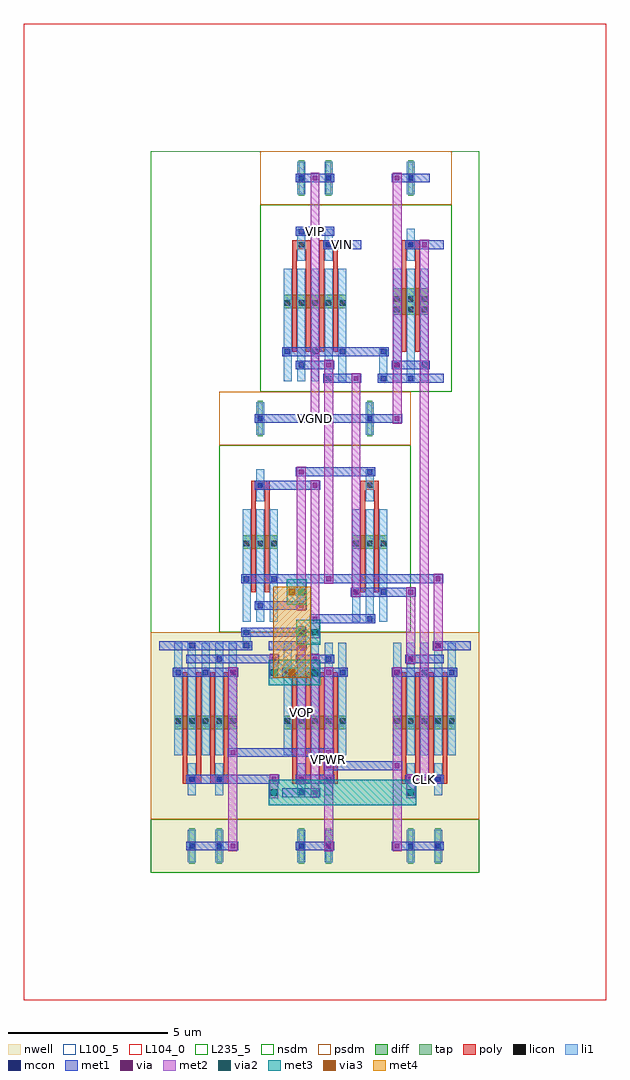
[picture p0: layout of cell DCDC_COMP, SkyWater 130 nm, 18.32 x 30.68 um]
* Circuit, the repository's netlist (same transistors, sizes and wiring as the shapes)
.subckt DCDC_COMP VPWR VGND VIN VIP VOP CLK
X0 VCM CLK VGND VGND  sky130_fd_pr__nfet_01v8 w=840000u l=150000u m=2
X1 VMP VIN VCM VGND  sky130_fd_pr__nfet_01v8 w=420000u l=150000u m=2
X2 VMN VIP VCM VGND  sky130_fd_pr__nfet_01v8 w=420000u l=150000u m=2
X3 VOP VON VMP VGND  sky130_fd_pr__nfet_01v8 w=420000u l=150000u m=2
X4 VON VOP VMN VGND  sky130_fd_pr__nfet_01v8 w=420000u l=150000u m=2
X5 VOP VON VPWR VPWR  sky130_fd_pr__pfet_01v8 w=420000u l=150000u m=2
X6 VON VOP VPWR VPWR  sky130_fd_pr__pfet_01v8 w=420000u l=150000u m=2
X7 VOP CLK VPWR VPWR  sky130_fd_pr__pfet_01v8 w=420000u l=150000u m=2
X8 VON CLK VPWR VPWR  sky130_fd_pr__pfet_01v8 w=420000u l=150000u m=2
X9 VMP CLK VPWR VPWR  sky130_fd_pr__pfet_01v8 w=420000u l=150000u m=2
X10 VMN CLK VPWR VPWR sky130_fd_pr__pfet_01v8 w=420000u l=150000u m=2
.ends DCDC_COMP

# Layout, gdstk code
from math import pi, radians
import gdstk
lib = gdstk.Library(unit=1e-6, precision=1e-09)
def R(c, l, rs):  # rectangles x0, y0, x1, y1
    for r in rs: c.add(gdstk.rectangle(r[:2], r[2:], *l))
def A(c, l, x, y, w, h, nx, ny, dx, dy):  # array of equal rectangles
    R(c, l, [(x+i*dx, y+j*dy, x+i*dx+w, y+j*dy+h) for i in range(nx) for j in range(ny)])
def P(c, l, *ps):  # polygons
    for p in ps: c.add(gdstk.Polygon(p, *l))
nwell = (64, 20)
diff = (65, 20)
tap = (65, 44)
poly = (66, 20)
licon = (66, 44)
li1 = (67, 20)
mcon = (67, 44)
met1 = (68, 20)
via = (68, 44)
met2 = (69, 20)
via2 = (69, 44)
met3 = (70, 20)
via3 = (70, 44)
met4 = (71, 20)
nsdm = (93, 44)
psdm = (94, 20)
L100_5 = (100, 5)
L104_0 = (104, 0)
L235_5 = (235, 5)

ccp_pmos_58853955_x1_y1_ = lib.new_cell('CCP_PMOS_58853955_X1_Y1_1653158392')
R(ccp_pmos_58853955_x1_y1_, nwell, [(0,0,3.44,7.56)])
R(ccp_pmos_58853955_x1_y1_, diff, [(0.735,2.625,2.705,3.045)])
R(ccp_pmos_58853955_x1_y1_, tap, [(1.205,6.16,1.375,7.28), (2.065,6.16,2.235,7.28)])
A(ccp_pmos_58853955_x1_y1_, poly, 1, 1.26, 0.15, 3.36, 4, 1, 0.43, 0)
R(ccp_pmos_58853955_x1_y1_, poly, [(1,4.485,1.58,4.755), (1.86,4.485,2.44,4.755)])
A(ccp_pmos_58853955_x1_y1_, licon, 0.775, 2.705, 0.17, 0.17, 3, 1, 0.43, 0)
A(ccp_pmos_58853955_x1_y1_, licon, 1.635, 2.705, 0.17, 0.17, 3, 1, 0.43, 0)
R(ccp_pmos_58853955_x1_y1_, licon, [(1.205,4.535,1.375,4.705), (2.065,4.535,2.235,4.705), (1.205,6.635,1.375,6.805), (2.065,6.635,2.235,6.805)])
A(ccp_pmos_58853955_x1_y1_, li1, 0.735, 0.335, 0.25, 3.53, 5, 1, 0.43, 0)
R(ccp_pmos_58853955_x1_y1_, li1, [(1.165,4.115,1.415,5.125), (2.025,4.115,2.275,5.125), (1.165,6.215,1.415,7.225), (2.025,6.215,2.275,7.225)])
A(ccp_pmos_58853955_x1_y1_, mcon, 0.775, 1.175, 0.17, 0.17, 3, 1, 0.86, 0)
R(ccp_pmos_58853955_x1_y1_, mcon, [(1.205,0.335,1.375,0.505), (2.065,0.755,2.235,0.925), (2.065,4.535,2.235,4.705), (1.205,4.955,1.375,5.125), (1.205,6.635,1.375,6.805), (2.065,6.635,2.235,6.805)])
R(ccp_pmos_58853955_x1_y1_, met1, [(0.26,0.28,1.46,0.56), (1.12,0.7,2.32,0.98), (0.69,1.12,2.75,1.4), (1.12,4.48,2.32,4.76), (0.69,4.9,1.89,5.18), (1.12,6.58,2.32,6.86)])
R(ccp_pmos_58853955_x1_y1_, via, [(1.215,0.345,1.365,0.495), (1.645,0.765,1.795,0.915), (2.075,1.185,2.225,1.335), (1.215,4.545,1.365,4.695), (1.645,4.965,1.795,5.115), (2.075,6.645,2.225,6.795)])
R(ccp_pmos_58853955_x1_y1_, met2, [(1.15,0.26,1.43,4.78), (1.58,0.68,1.86,5.2), (2.01,1.1,2.29,6.88)])
R(ccp_pmos_58853955_x1_y1_, nsdm, [(0,5.88,3.44,7.56)])
R(ccp_pmos_58853955_x1_y1_, psdm, [(0,0,3.44,5.88)])
R(ccp_pmos_58853955_x1_y1_, L100_5, [(0,0,3.44,7.56)])

cmc_pmos_23131506_x1_y1_ = lib.new_cell('CMC_PMOS_23131506_X1_Y1_1653158394')
R(cmc_pmos_23131506_x1_y1_, nwell, [(0,0,3.44,7.56)])
R(cmc_pmos_23131506_x1_y1_, diff, [(0.735,2.625,2.705,3.045)])
R(cmc_pmos_23131506_x1_y1_, tap, [(1.205,6.16,1.375,7.28), (2.065,6.16,2.235,7.28)])
A(cmc_pmos_23131506_x1_y1_, poly, 1, 1.26, 0.15, 3.36, 4, 1, 0.43, 0)
R(cmc_pmos_23131506_x1_y1_, poly, [(1,4.485,1.58,4.755), (1.86,4.485,2.44,4.755)])
A(cmc_pmos_23131506_x1_y1_, licon, 0.775, 2.705, 0.17, 0.17, 3, 1, 0.43, 0)
A(cmc_pmos_23131506_x1_y1_, licon, 1.635, 2.705, 0.17, 0.17, 3, 1, 0.43, 0)
R(cmc_pmos_23131506_x1_y1_, licon, [(1.205,4.535,1.375,4.705), (2.065,4.535,2.235,4.705), (1.205,6.635,1.375,6.805), (2.065,6.635,2.235,6.805)])
A(cmc_pmos_23131506_x1_y1_, li1, 0.735, 0.335, 0.25, 3.53, 5, 1, 0.43, 0)
R(cmc_pmos_23131506_x1_y1_, li1, [(1.165,4.115,1.415,5.125), (2.025,4.115,2.275,5.125), (1.165,6.215,1.415,7.225), (2.025,6.215,2.275,7.225)])
A(cmc_pmos_23131506_x1_y1_, mcon, 0.775, 1.175, 0.17, 0.17, 3, 1, 0.86, 0)
R(cmc_pmos_23131506_x1_y1_, mcon, [(1.205,0.335,1.375,0.505), (2.065,0.755,2.235,0.925), (1.205,4.535,1.375,4.705), (2.065,4.535,2.235,4.705), (1.205,6.635,1.375,6.805), (2.065,6.635,2.235,6.805)])
R(cmc_pmos_23131506_x1_y1_, met1, [(0.26,0.28,1.46,0.56), (1.12,0.7,2.32,0.98), (0.69,1.12,2.75,1.4), (1.12,4.48,2.32,4.76), (1.12,6.58,2.75,6.86)])
R(cmc_pmos_23131506_x1_y1_, via, [(2.505,1.185,2.655,1.335), (2.505,6.645,2.655,6.795)])
R(cmc_pmos_23131506_x1_y1_, met2, [(2.44,1.1,2.72,6.88)])
R(cmc_pmos_23131506_x1_y1_, nsdm, [(0,5.88,3.44,7.56)])
R(cmc_pmos_23131506_x1_y1_, psdm, [(0,0,3.44,5.88)])
R(cmc_pmos_23131506_x1_y1_, L100_5, [(0,0,3.44,7.56)])

ccp_s_nmos_b_5782581_x1_ = lib.new_cell('CCP_S_NMOS_B_5782581_X1_Y1_1653158393')
R(ccp_s_nmos_b_5782581_x1_, diff, [(0.735,2.625,1.845,3.045), (4.175,2.625,5.285,3.045)])
R(ccp_s_nmos_b_5782581_x1_, tap, [(1.205,6.16,1.375,7.28), (4.645,6.16,4.815,7.28)])
R(ccp_s_nmos_b_5782581_x1_, poly, [(1,1.26,1.15,4.62), (1.43,1.26,1.58,4.62), (4.44,1.26,4.59,4.62), (4.87,1.26,5.02,4.62), (1,4.485,1.58,4.755), (4.44,4.485,5.02,4.755)])
A(ccp_s_nmos_b_5782581_x1_, licon, 0.775, 2.705, 0.17, 0.17, 3, 1, 0.43, 0)
A(ccp_s_nmos_b_5782581_x1_, licon, 4.215, 2.705, 0.17, 0.17, 3, 1, 0.43, 0)
R(ccp_s_nmos_b_5782581_x1_, licon, [(1.205,4.535,1.375,4.705), (4.645,4.535,4.815,4.705), (1.205,6.635,1.375,6.805), (4.645,6.635,4.815,6.805)])
A(ccp_s_nmos_b_5782581_x1_, li1, 0.735, 0.335, 0.25, 3.53, 3, 1, 0.43, 0)
A(ccp_s_nmos_b_5782581_x1_, li1, 4.175, 0.335, 0.25, 3.53, 3, 1, 0.43, 0)
R(ccp_s_nmos_b_5782581_x1_, li1, [(1.165,4.115,1.415,5.125), (4.605,4.115,4.855,5.125), (1.165,6.215,1.415,7.225), (4.605,6.215,4.855,7.225)])
R(ccp_s_nmos_b_5782581_x1_, mcon, [(1.205,0.335,1.375,0.505), (4.645,0.755,4.815,0.925), (0.775,1.175,0.945,1.345), (1.635,1.175,1.805,1.345), (4.215,1.595,4.385,1.765), (5.075,1.595,5.245,1.765), (4.645,4.535,4.815,4.705), (1.205,4.955,1.375,5.125), (1.205,6.635,1.375,6.805), (4.645,6.635,4.815,6.805)])
R(ccp_s_nmos_b_5782581_x1_, met1, [(1.12,0.28,3.18,0.56), (3.27,0.7,4.9,0.98), (0.69,1.12,1.89,1.4), (4.13,1.54,5.33,1.82), (2.84,4.48,4.9,4.76), (1.12,4.9,3.61,5.18), (1.12,6.58,4.9,6.86)])
R(ccp_s_nmos_b_5782581_x1_, via, [(2.935,0.345,3.085,0.495), (3.365,0.765,3.515,0.915), (2.935,4.545,3.085,4.695), (3.365,4.965,3.515,5.115)])
R(ccp_s_nmos_b_5782581_x1_, met2, [(2.87,0.26,3.15,4.78), (3.3,0.68,3.58,5.2)])
R(ccp_s_nmos_b_5782581_x1_, nsdm, [(0,0,6.02,5.88)])
R(ccp_s_nmos_b_5782581_x1_, psdm, [(0,5.88,6.02,7.56)])
R(ccp_s_nmos_b_5782581_x1_, L100_5, [(0,0,6.02,7.56)])

dp_nmos_b_93310865_x1_y1 = lib.new_cell('DP_NMOS_B_93310865_X1_Y1_1653158395')
R(dp_nmos_b_93310865_x1_y1, diff, [(0.735,2.625,2.705,3.045)])
R(dp_nmos_b_93310865_x1_y1, tap, [(1.205,6.16,1.375,7.28), (2.065,6.16,2.235,7.28)])
A(dp_nmos_b_93310865_x1_y1, poly, 1, 1.26, 0.15, 3.36, 4, 1, 0.43, 0)
R(dp_nmos_b_93310865_x1_y1, poly, [(1,4.485,1.58,4.755), (1.86,4.485,2.44,4.755)])
A(dp_nmos_b_93310865_x1_y1, licon, 0.775, 2.705, 0.17, 0.17, 3, 1, 0.43, 0)
A(dp_nmos_b_93310865_x1_y1, licon, 1.635, 2.705, 0.17, 0.17, 3, 1, 0.43, 0)
R(dp_nmos_b_93310865_x1_y1, licon, [(1.205,4.535,1.375,4.705), (2.065,4.535,2.235,4.705), (1.205,6.635,1.375,6.805), (2.065,6.635,2.235,6.805)])
A(dp_nmos_b_93310865_x1_y1, li1, 0.735, 0.335, 0.25, 3.53, 5, 1, 0.43, 0)
R(dp_nmos_b_93310865_x1_y1, li1, [(1.165,4.115,1.415,5.125), (2.025,4.115,2.275,5.125), (1.165,6.215,1.415,7.225), (2.025,6.215,2.275,7.225)])
A(dp_nmos_b_93310865_x1_y1, mcon, 0.775, 1.175, 0.17, 0.17, 3, 1, 0.86, 0)
R(dp_nmos_b_93310865_x1_y1, mcon, [(1.205,0.335,1.375,0.505), (2.065,0.755,2.235,0.925), (1.205,4.535,1.375,4.705), (2.065,4.955,2.235,5.125), (1.205,6.635,1.375,6.805), (2.065,6.635,2.235,6.805)])
R(dp_nmos_b_93310865_x1_y1, met1, [(0.26,0.28,1.46,0.56), (1.12,0.7,2.32,0.98), (0.69,1.12,2.75,1.4), (0.26,4.48,1.46,4.76), (1.12,4.9,2.32,5.18), (1.12,6.58,2.32,6.86)])
R(dp_nmos_b_93310865_x1_y1, nsdm, [(0,0,3.44,5.88)])
R(dp_nmos_b_93310865_x1_y1, psdm, [(0,5.88,3.44,7.56)])
R(dp_nmos_b_93310865_x1_y1, L100_5, [(0,0,3.44,7.56)])

nmos_s_93862694_x1_y1_16 = lib.new_cell('NMOS_S_93862694_X1_Y1_1653158396')
R(nmos_s_93862694_x1_y1_16, diff, [(0.735,2.415,1.845,3.255)])
R(nmos_s_93862694_x1_y1_16, tap, [(1.205,6.16,1.375,7.28)])
R(nmos_s_93862694_x1_y1_16, poly, [(1,1.26,1.15,4.62), (1.43,1.26,1.58,4.62), (1,4.485,1.58,4.755)])
A(nmos_s_93862694_x1_y1_16, licon, 0.775, 2.495, 0.17, 0.17, 3, 2, 0.43, 0.34)
R(nmos_s_93862694_x1_y1_16, licon, [(1.205,4.535,1.375,4.705), (1.205,6.635,1.375,6.805)])
A(nmos_s_93862694_x1_y1_16, li1, 0.735, 0.335, 0.25, 3.53, 3, 1, 0.43, 0)
R(nmos_s_93862694_x1_y1_16, li1, [(1.165,4.115,1.415,5.125), (1.165,6.215,1.415,7.225)])
R(nmos_s_93862694_x1_y1_16, mcon, [(1.205,0.335,1.375,0.505), (0.775,0.755,0.945,0.925), (1.635,0.755,1.805,0.925), (1.205,4.535,1.375,4.705), (1.205,6.635,1.375,6.805)])
R(nmos_s_93862694_x1_y1_16, met1, [(0.26,0.28,1.46,0.56), (0.69,0.7,1.89,0.98), (0.26,4.48,1.46,4.76), (0.69,6.58,1.89,6.86)])
R(nmos_s_93862694_x1_y1_16, via, [(1.645,0.765,1.795,0.915), (1.645,6.645,1.795,6.795)])
R(nmos_s_93862694_x1_y1_16, met2, [(1.58,0.68,1.86,6.88)])
R(nmos_s_93862694_x1_y1_16, nsdm, [(0,0,2.58,5.88)])
R(nmos_s_93862694_x1_y1_16, psdm, [(0,5.88,2.58,7.56)])
R(nmos_s_93862694_x1_y1_16, L100_5, [(0,0,2.58,7.56)])

dcdc_comp = lib.new_cell('DCDC_COMP')
R(dcdc_comp, li1, [(2.885,7.055,3.135,7.225), (2.885,7.055,3.135,7.225), (2.885,7.055,3.135,7.225), (2.885,7.055,3.135,7.225), (2.885,7.14,3.135,7.56), (2.885,7.475,3.135,7.645), (2.885,7.475,3.135,7.645), (2.885,7.475,3.135,7.645), (2.885,7.475,3.135,7.645), (7.185,15.455,7.435,15.625), (7.185,15.455,7.435,15.625), (7.185,15.54,7.435,16.38), (7.185,16.295,7.435,16.465), (7.185,16.295,7.435,16.465)])
R(dcdc_comp, mcon, [(2.925,7.055,3.095,7.225), (2.925,7.055,3.095,7.225), (2.925,7.055,3.095,7.225), (2.925,7.055,3.095,7.225), (2.925,7.475,3.095,7.645), (2.925,7.475,3.095,7.645), (2.925,7.475,3.095,7.645), (2.925,7.475,3.095,7.645), (7.225,15.455,7.395,15.625), (7.225,15.455,7.395,15.625), (7.225,16.295,7.395,16.465), (7.225,16.295,7.395,16.465)])
R(dcdc_comp, met1, [(2.15,2.8,3.87,3.08), (3.71,2.8,4.03,3.08), (3.71,2.8,4.03,3.08), (3.71,2.8,4.03,3.08), (3.71,2.8,4.03,3.08), (8.01,2.8,8.33,3.08), (8.01,2.8,8.33,3.08), (8.01,2.8,8.33,3.08), (8.01,2.8,8.33,3.08), (8.44,2.8,8.76,3.08), (8.44,2.8,8.76,3.08), (5.43,3.22,5.75,3.5), (5.43,3.22,5.75,3.5), (5.43,3.22,5.75,3.5), (5.43,3.22,5.75,3.5), (5.59,3.22,7.74,3.5), (7.58,3.22,7.9,3.5), (7.58,3.22,7.9,3.5), (7.58,3.22,7.9,3.5), (7.58,3.22,7.9,3.5), (2.42,3.64,2.74,3.92), (2.42,3.64,2.74,3.92), (2.58,3.64,5.59,3.92), (5.43,3.64,5.75,3.92), (5.43,3.64,5.75,3.92), (2.15,6.58,3.87,6.86), (3.71,6.58,4.03,6.86), (3.71,6.58,4.03,6.86), (3.71,6.58,4.03,6.86), (3.71,6.58,4.03,6.86), (8.01,6.58,8.33,6.86), (8.01,6.58,8.33,6.86), (8.01,6.58,8.33,6.86), (8.01,6.58,8.33,6.86), (1.29,7,3.01,7.28), (2.84,7,3.18,7.28), (2.84,7,3.18,7.28), (2.84,7,3.18,7.28), (2.84,7,3.18,7.28), (8.87,7,9.19,7.28), (8.87,7,9.19,7.28), (8.87,7,9.19,7.28), (8.87,7,9.19,7.28), (2.84,7.42,3.18,7.7), (2.84,7.42,3.18,7.7), (2.84,7.42,3.18,7.7), (2.84,7.42,3.18,7.7), (3.01,7.42,4.73,7.7), (4.57,7.42,4.89,7.7), (4.57,7.42,4.89,7.7), (4.57,7.42,4.89,7.7), (4.57,7.42,4.89,7.7), (6.29,8.68,6.61,8.96), (6.29,8.68,6.61,8.96), (7.31,8.68,8.17,8.96), (8.01,8.68,8.33,8.96), (8.01,8.68,8.33,8.96), (8.01,8.68,8.33,8.96), (8.01,8.68,8.33,8.96), (3.87,9.1,9.03,9.38), (5.43,9.1,5.75,9.38), (5.43,9.1,5.75,9.38), (8.87,9.1,9.19,9.38), (8.87,9.1,9.19,9.38), (8.87,9.1,9.19,9.38), (8.87,9.1,9.19,9.38), (5,14.14,5.32,14.42), (5,14.14,5.32,14.42), (5,14.14,5.32,14.42), (5,14.14,5.32,14.42), (6.88,14.14,7.74,14.42), (7.58,14.14,7.9,14.42), (7.58,14.14,7.9,14.42), (6.29,15.4,6.61,15.68), (6.29,15.4,6.61,15.68), (7.14,15.4,7.48,15.68), (7.14,15.4,7.48,15.68), (7.31,15.4,8.17,15.68), (5.43,15.82,5.75,16.1), (5.43,15.82,5.75,16.1), (6.02,16.24,7.31,16.52), (7.14,16.24,7.48,16.52), (7.14,16.24,7.48,16.52), (8.44,19.6,8.76,19.88), (8.44,19.6,8.76,19.88), (5,21.7,5.32,21.98), (5,21.7,5.32,21.98), (5,21.7,5.32,21.98), (5,21.7,5.32,21.98)])
P(dcdc_comp, met1, [(0,0),(0,0),(0,0),(0,0)],
  [(0,0),(0,0),(0,0),(0,0)],
  [(0,0),(0,0),(0,0),(0,0)],
  [(0,0),(0,0),(0,0),(0,0)],
  [(0,0),(0,0),(0,0),(0,0)],
  [(0,0),(0,0),(0,0),(0,0)],
  [(0,0),(0,0),(0,0),(0,0)],
  [(0,0),(0,0),(0,0),(0,0)],
  [(0,0),(0,0),(0,0),(0,0)],
  [(0,0),(0,0),(0,0),(0,0)],
  [(0,0),(0,0),(0,0),(0,0)],
  [(0,0),(0,0),(0,0),(0,0)],
  [(0,0),(0,0),(0,0),(0,0)],
  [(0,0),(0,0),(0,0),(0,0)],
  [(0,0),(0,0),(0,0),(0,0)],
  [(0,0),(0,0),(0,0),(0,0)],
  [(0,0),(0,0),(0,0),(0,0)],
  [(0,0),(0,0),(0,0),(0,0)],
  [(0,0),(0,0),(0,0),(0,0)],
  [(0,0),(0,0),(0,0),(0,0)],
  [(0,0),(0,0),(0,0),(0,0)])
R(dcdc_comp, via, [(3.795,2.865,3.945,3.015), (3.795,2.865,3.945,3.015), (3.795,2.865,3.945,3.015), (3.795,2.865,3.945,3.015), (8.095,2.865,8.245,3.015), (8.095,2.865,8.245,3.015), (8.095,2.865,8.245,3.015), (8.095,2.865,8.245,3.015), (8.525,2.865,8.675,3.015), (8.525,2.865,8.675,3.015), (5.515,3.285,5.665,3.435), (5.515,3.285,5.665,3.435), (5.515,3.285,5.665,3.435), (5.515,3.285,5.665,3.435), (7.665,3.285,7.815,3.435), (7.665,3.285,7.815,3.435), (7.665,3.285,7.815,3.435), (7.665,3.285,7.815,3.435), (2.505,3.705,2.655,3.855), (2.505,3.705,2.655,3.855), (5.515,3.705,5.665,3.855), (5.515,3.705,5.665,3.855), (3.795,6.645,3.945,6.795), (3.795,6.645,3.945,6.795), (3.795,6.645,3.945,6.795), (3.795,6.645,3.945,6.795), (8.095,6.645,8.245,6.795), (8.095,6.645,8.245,6.795), (8.095,6.645,8.245,6.795), (8.095,6.645,8.245,6.795), (8.955,7.065,9.105,7.215), (8.955,7.065,9.105,7.215), (8.955,7.065,9.105,7.215), (8.955,7.065,9.105,7.215), (4.655,7.485,4.805,7.635), (4.655,7.485,4.805,7.635), (4.655,7.485,4.805,7.635), (4.655,7.485,4.805,7.635), (6.375,8.745,6.525,8.895), (6.375,8.745,6.525,8.895), (8.095,8.745,8.245,8.895), (8.095,8.745,8.245,8.895), (8.095,8.745,8.245,8.895), (8.095,8.745,8.245,8.895), (5.515,9.165,5.665,9.315), (5.515,9.165,5.665,9.315), (8.955,9.165,9.105,9.315), (8.955,9.165,9.105,9.315), (8.955,9.165,9.105,9.315), (8.955,9.165,9.105,9.315), (5.085,14.205,5.235,14.355), (5.085,14.205,5.235,14.355), (5.085,14.205,5.235,14.355), (5.085,14.205,5.235,14.355), (7.665,14.205,7.815,14.355), (7.665,14.205,7.815,14.355), (6.375,15.465,6.525,15.615), (6.375,15.465,6.525,15.615), (5.515,15.885,5.665,16.035), (5.515,15.885,5.665,16.035), (8.525,19.665,8.675,19.815), (8.525,19.665,8.675,19.815), (5.085,21.765,5.235,21.915), (5.085,21.765,5.235,21.915), (5.085,21.765,5.235,21.915), (5.085,21.765,5.235,21.915)])
R(dcdc_comp, met2, [(3.73,2.335,4.01,2.705), (3.73,2.335,4.01,2.705), (3.73,2.335,4.01,2.705), (3.73,2.335,4.01,2.705), (8.03,2.335,8.31,2.705), (8.03,2.335,8.31,2.705), (8.03,2.335,8.31,2.705), (8.03,2.335,8.31,2.705), (3.73,2.52,4.01,2.94), (8.03,2.52,8.31,2.94), (3.73,2.78,4.01,3.1), (3.73,2.78,4.01,3.1), (3.73,2.78,4.01,3.1), (3.73,2.78,4.01,3.1), (8.03,2.78,8.31,3.1), (8.03,2.78,8.31,3.1), (8.03,2.78,8.31,3.1), (8.03,2.78,8.31,3.1), (8.46,2.78,8.74,3.1), (8.46,2.78,8.74,3.1), (8.46,2.94,8.74,19.74), (5.45,3.2,5.73,3.52), (5.45,3.2,5.73,3.52), (5.45,3.2,5.73,3.52), (5.45,3.2,5.73,3.52), (7.6,3.2,7.88,3.52), (7.6,3.2,7.88,3.52), (7.6,3.2,7.88,3.52), (7.6,3.2,7.88,3.52), (2.44,3.62,2.72,3.94), (2.44,3.62,2.72,3.94), (5.45,3.62,5.73,3.94), (5.45,3.62,5.73,3.94), (3.73,6.115,4.01,6.485), (3.73,6.115,4.01,6.485), (3.73,6.115,4.01,6.485), (3.73,6.115,4.01,6.485), (5.02,6.115,5.3,6.485), (5.02,6.115,5.3,6.485), (5.02,6.115,5.3,6.485), (5.02,6.115,5.3,6.485), (3.73,6.3,4.01,6.72), (3.73,6.56,4.01,6.88), (3.73,6.56,4.01,6.88), (3.73,6.56,4.01,6.88), (3.73,6.56,4.01,6.88), (8.03,6.56,8.31,6.88), (8.03,6.56,8.31,6.88), (8.03,6.56,8.31,6.88), (8.03,6.56,8.31,6.88), (8.03,6.72,8.31,8.82), (8.89,6.98,9.17,7.3), (8.89,6.98,9.17,7.3), (8.89,6.98,9.17,7.3), (8.89,6.98,9.17,7.3), (4.59,7.14,4.87,7.56), (8.89,7.14,9.17,9.24), (4.59,7.375,4.87,7.745), (4.59,7.375,4.87,7.745), (5.02,7.375,5.3,7.745), (5.02,7.375,5.3,7.745), (4.59,7.4,4.87,7.72), (4.59,7.4,4.87,7.72), (4.59,7.4,4.87,7.72), (4.59,7.4,4.87,7.72), (5.02,7.56,5.3,7.98), (4.59,8.635,4.87,9.005), (6.31,8.66,6.59,8.98), (6.31,8.66,6.59,8.98), (8.03,8.66,8.31,8.98), (8.03,8.66,8.31,8.98), (8.03,8.66,8.31,8.98), (8.03,8.66,8.31,8.98), (6.31,8.82,6.59,15.54), (5.45,9.08,5.73,9.4), (5.45,9.08,5.73,9.4), (8.89,9.08,9.17,9.4), (8.89,9.08,9.17,9.4), (8.89,9.08,9.17,9.4), (8.89,9.08,9.17,9.4), (5.45,9.24,5.73,15.96), (5.02,14.12,5.3,14.44), (5.02,14.12,5.3,14.44), (5.02,14.12,5.3,14.44), (5.02,14.12,5.3,14.44), (7.6,14.12,7.88,14.44), (7.6,14.12,7.88,14.44), (5.02,14.28,5.3,21.84), (7.6,14.28,7.88,15.96), (6.31,15.38,6.59,15.7), (6.31,15.38,6.59,15.7), (5.45,15.8,5.73,16.12), (5.45,15.8,5.73,16.12), (8.46,19.58,8.74,19.9), (8.46,19.58,8.74,19.9), (5.02,21.68,5.3,22), (5.02,21.68,5.3,22), (5.02,21.68,5.3,22), (5.02,21.68,5.3,22)])
P(dcdc_comp, met2, [(0,0),(0,0),(0,0),(0,0)],
  [(0,0),(0,0),(0,0),(0,0)],
  [(0,0),(0,0),(0,0),(0,0)],
  [(0,0),(0,0),(0,0),(0,0)],
  [(0,0),(0,0),(0,0),(0,0)],
  [(0,0),(0,0),(0,0),(0,0)],
  [(0,0),(0,0),(0,0),(0,0)],
  [(0,0),(0,0),(0,0),(0,0)],
  [(0,0),(0,0),(0,0),(0,0)],
  [(0,0),(0,0),(0,0),(0,0)],
  [(0,0),(0,0),(0,0),(0,0)])
R(dcdc_comp, via2, [(3.77,2.42,3.97,2.62), (3.77,2.42,3.97,2.62), (3.77,2.42,3.97,2.62), (3.77,2.42,3.97,2.62), (8.07,2.42,8.27,2.62), (8.07,2.42,8.27,2.62), (8.07,2.42,8.27,2.62), (8.07,2.42,8.27,2.62), (3.77,6.2,3.97,6.4), (3.77,6.2,3.97,6.4), (3.77,6.2,3.97,6.4), (3.77,6.2,3.97,6.4), (5.06,6.2,5.26,6.4), (5.06,6.2,5.26,6.4), (5.06,6.2,5.26,6.4), (5.06,6.2,5.26,6.4), (4.63,7.46,4.83,7.66), (4.63,7.46,4.83,7.66), (5.06,7.46,5.26,7.66), (5.06,7.46,5.26,7.66), (4.63,8.72,4.83,8.92)])
R(dcdc_comp, met3, [(3.705,2.12,4.035,2.92), (3.705,2.12,4.035,2.92), (3.705,2.12,4.035,2.92), (3.705,2.12,4.035,2.92), (3.87,2.12,8.17,2.92), (8.005,2.12,8.335,2.92), (8.005,2.12,8.335,2.92), (8.005,2.12,8.335,2.92), (8.005,2.12,8.335,2.92), (3.705,5.9,4.035,6.7), (3.705,5.9,4.035,6.7), (3.705,5.9,4.035,6.7), (3.705,5.9,4.035,6.7), (3.87,5.9,5.16,6.7), (4.275,5.9,4.605,6.7), (4.275,5.9,4.605,6.7), (4.995,5.9,5.325,6.7), (4.995,5.9,5.325,6.7), (4.995,5.9,5.325,6.7), (4.995,5.9,5.325,6.7), (4.565,7.16,4.895,7.96), (4.565,7.16,4.895,7.96), (4.73,7.16,5.16,7.96), (4.995,7.16,5.325,7.96), (4.995,7.16,5.325,7.96), (4.275,8.42,4.605,9.22), (4.435,8.42,4.735,9.22), (4.565,8.42,4.895,9.22)])
R(dcdc_comp, via3, [(4.34,6.2,4.54,6.4), (4.34,6.2,4.54,6.4), (4.34,8.72,4.54,8.92)])
R(dcdc_comp, met4, [(3.85,6.135,5.03,6.465), (3.85,6.135,5.03,6.465), (3.85,6.3,5.03,8.82), (3.85,8.655,5.03,8.985)])
R(dcdc_comp, L104_0, [(-4,-4,14.32,26.68)])
R(dcdc_comp, L235_5, [(0,0,10.32,22.68)])
dcdc_comp.add(gdstk.Reference(ccp_pmos_58853955_x1_y1_, (3.44,7.56), x_reflection=True))
dcdc_comp.add(gdstk.Reference(cmc_pmos_23131506_x1_y1_, (10.32,7.56), rotation=pi))
dcdc_comp.add(gdstk.Reference(cmc_pmos_23131506_x1_y1_, (0,7.56), x_reflection=True))
dcdc_comp.add(gdstk.Reference(ccp_s_nmos_b_5782581_x1_, (8.17,7.56), rotation=pi, x_reflection=True))
dcdc_comp.add(gdstk.Reference(dp_nmos_b_93310865_x1_y1, (6.88,15.12), rotation=pi, x_reflection=True))
dcdc_comp.add(gdstk.Reference(nmos_s_93862694_x1_y1_16, (9.46,15.12), rotation=pi, x_reflection=True))
dcdc_comp.add(gdstk.Label('VOP', (4.73,5.04), layer=69, texttype=5))
dcdc_comp.add(gdstk.Label('VON', (5.16,4.62), layer=69, texttype=5))
dcdc_comp.add(gdstk.Label('VPWR', (5.59,3.57), layer=69, texttype=5))
dcdc_comp.add(gdstk.Label('CLK', (8.6,2.94), layer=68, texttype=5))
dcdc_comp.add(gdstk.Label('VGND', (5.16,14.28), layer=68, texttype=5))
dcdc_comp.add(gdstk.Label('VIN', (6.02,19.74), layer=68, texttype=5))
dcdc_comp.add(gdstk.Label('VIP', (5.16,20.16), layer=68, texttype=5))

lib.write_gds('DCDC_COMP.gds')
